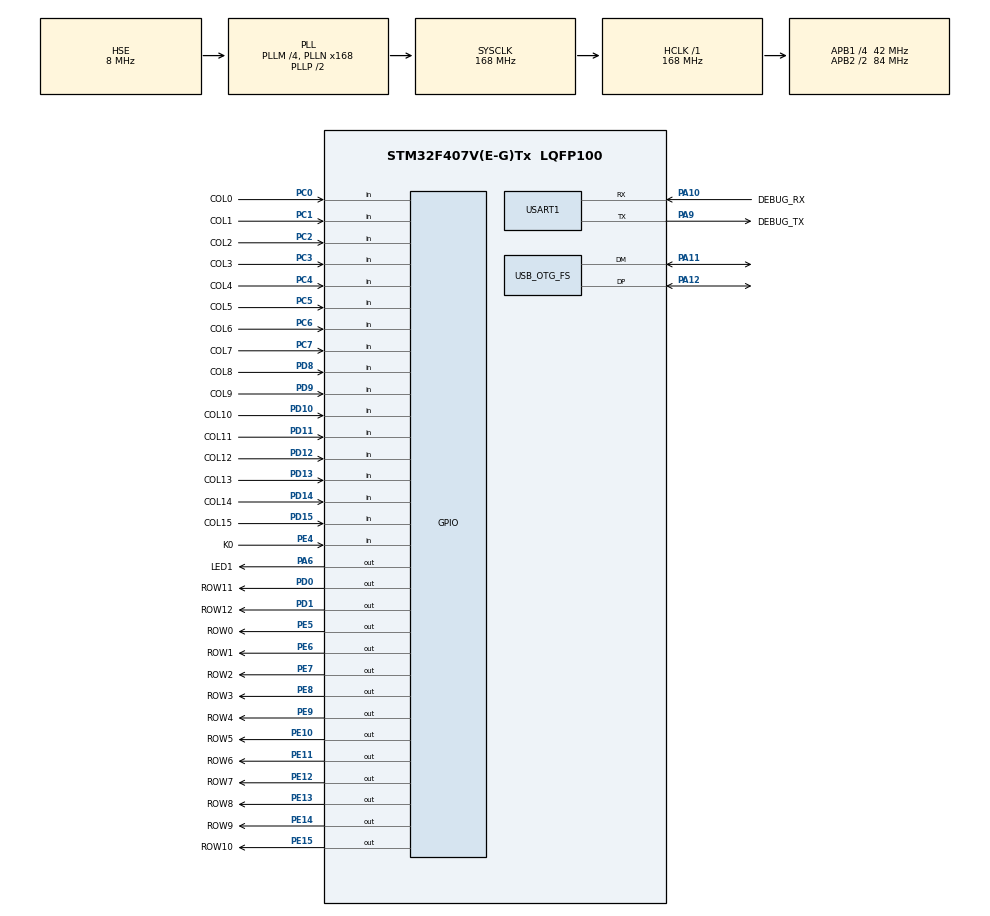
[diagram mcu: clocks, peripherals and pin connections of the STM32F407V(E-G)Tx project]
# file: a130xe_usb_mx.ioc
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Mcu.Family=STM32F4
Mcu.Name=STM32F407V(E-G)Tx
Mcu.Package=LQFP100
NVIC.OTG_FS_IRQn=true\:0\:0\:false\:false\:true\:false\:true
NVIC.PriorityGroup=NVIC_PRIORITYGROUP_4
PA10.GPIO_Label=DEBUG_RX
PA10.Mode=Asynchronous
PA10.Signal=USART1_RX
PA11.Mode=Device_Only
PA11.Signal=USB_OTG_FS_DM
PA12.Mode=Device_Only
PA12.Signal=USB_OTG_FS_DP
PA6.GPIO_Label=LED1
PA6.PinState=GPIO_PIN_SET
PA6.Signal=GPIO_Output
PA9.GPIO_Label=DEBUG_TX
PA9.Mode=Asynchronous
PA9.Signal=USART1_TX
PC0.GPIO_Label=COL0
PC0.Signal=GPIO_Input
PC1.GPIO_Label=COL1
PC1.Signal=GPIO_Input
PC2.GPIO_Label=COL2
PC2.Signal=GPIO_Input
PC3.GPIO_Label=COL3
PC3.Signal=GPIO_Input
PC4.GPIO_Label=COL4
PC4.Signal=GPIO_Input
PC5.GPIO_Label=COL5
PC5.Signal=GPIO_Input
PC6.GPIO_Label=COL6
PC6.Signal=GPIO_Input
PC7.GPIO_Label=COL7
PC7.Signal=GPIO_Input
PD0.GPIO_Label=ROW11
PD0.Signal=GPIO_Output
PD1.GPIO_Label=ROW12
PD1.Signal=GPIO_Output
PD10.GPIO_Label=COL10
PD10.Signal=GPIO_Input
PD11.GPIO_Label=COL11
PD11.Signal=GPIO_Input
PD12.GPIO_Label=COL12
PD12.Signal=GPIO_Input
PD13.GPIO_Label=COL13
PD13.Signal=GPIO_Input
PD14.GPIO_Label=COL14
PD14.Signal=GPIO_Input
PD15.GPIO_Label=COL15
PD15.Signal=GPIO_Input
PD8.GPIO_Label=COL8
PD8.Signal=GPIO_Input
PD9.GPIO_Label=COL9
PD9.Signal=GPIO_Input
PE10.GPIO_Label=ROW5
PE10.Signal=GPIO_Output
PE11.GPIO_Label=ROW6
PE11.Signal=GPIO_Output
PE12.GPIO_Label=ROW7
PE12.Signal=GPIO_Output
PE13.GPIO_Label=ROW8
PE13.Signal=GPIO_Output
PE14.GPIO_Label=ROW9
PE14.Signal=GPIO_Output
PE15.GPIO_Label=ROW10
PE15.Signal=GPIO_Output
PE4.GPIO_Label=K0
PE4.Signal=GPIO_Input
PE5.GPIO_Label=ROW0
PE5.Signal=GPIO_Output
PE6.GPIO_Label=ROW1
PE6.Signal=GPIO_Output
PE7.GPIO_Label=ROW2
PE7.Signal=GPIO_Output
PE8.GPIO_Label=ROW3
PE8.Signal=GPIO_Output
PE9.GPIO_Label=ROW4
PE9.Signal=GPIO_Output
PH0-OSC_IN.Mode=HSE-External-Oscillator
PH0-OSC_IN.Signal=RCC_OSC_IN
PH1-OSC_OUT.Mode=HSE-External-Oscillator
PH1-OSC_OUT.Signal=RCC_OSC_OUT
ProjectManager.HeapSize=0x200
ProjectManager.StackSize=0x400
ProjectManager.TargetToolchain=Makefile
RCC.48MHZClocksFreq_Value=48000000
RCC.AHBFreq_Value=168000000
RCC.APB1CLKDivider=RCC_HCLK_DIV4
RCC.APB1Freq_Value=42000000
RCC.APB1TimFreq_Value=84000000
RCC.APB2CLKDivider=RCC_HCLK_DIV2
RCC.APB2Freq_Value=84000000
RCC.APB2TimFreq_Value=168000000
RCC.CortexFreq_Value=168000000
RCC.HCLKFreq_Value=168000000
RCC.HSE_VALUE=8000000
RCC.HSI_VALUE=16000000
RCC.LSE_VALUE=32768
RCC.PLLM=4
RCC.PLLN=168
RCC.PLLQ=7
RCC.SYSCLKFreq_VALUE=168000000
RCC.SYSCLKSource=RCC_SYSCLKSOURCE_PLLCLK
RCC.VCOOutputFreq_Value=336000000
USART1.VirtualMode=VM_ASYNC
USB_DEVICE.CLASS_NAME_FS=HID
USB_DEVICE.MANUFACTURER_STRING-HID_FS=RetroBitLab
USB_DEVICE.PRODUCT_STRING_HID_FS=Keyboard Human interface
USB_DEVICE.USBD_DEBUG_LEVEL-HID_FS=3
USB_DEVICE.VirtualMode-HID_FS=Hid
USB_DEVICE.VirtualModeFS=Hid_FS
USB_OTG_FS.VirtualMode=Device_Only
VP_USB_DEVICE_VS_USB_DEVICE_HID_FS.Mode=HID_FS
board=custom

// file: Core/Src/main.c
/* USER CODE BEGIN Header */
/**
  ******************************************************************************
  * @file           : main.c
  * @brief          : Main program body
  ******************************************************************************
  * @attention
  *
  * Copyright (c) 2022 STMicroelectronics.
  * All rights reserved.
  *
  * This software is licensed under terms that can be found in the LICENSE file
  * in the root directory of this software component.
  * If no LICENSE file comes with this software, it is provided AS-IS.
  *
  ******************************************************************************
  */
/* USER CODE END Header */
#include <stdio.h>
#include <string.h>
#include "stm32f4xx_ll_gpio.h"
#include "usbd_hid.h"
#include "syscall.h"
#include "debug.h"
#include "main.h"
#include "usb_device.h"
#include "keyboard.h"
#include "host.h"
#include "config.h"

static UART_HandleTypeDef huart1;
static int debuglevel = DBG_VERBOSE;

__weak void matrix_init(void) { };

static void SystemClock_Config(void);
static void MX_GPIO_Init(void);
static void MX_USART1_UART_Init(void);

#if defined(__ATARI__)
#	define KEYBOARD_INTERFACE "ATARI XL/XE"
#elif defined(__AMIGA__)
#	define KEYBOARD_INTERFACE "AMIGA COMMODORE COMPUTERS"
#else
#	error "NO PLATFORM DEFINED"
#endif

static void banner(void)
{
	DBG_I("STM32 KEYBOARD CORE INTERFACE BOARD for " KEYBOARD_INTERFACE "\r\n");
	DBG_I("(C) RetroBit Lab 2021/2022 written by Gianluca Renzi <icjtqr@gmail.com>\r\n");
}

void led_toggle(void)
{
	static int ledval = 0;
	if (ledval == 0)
	{
		LED_ON();
	}
	else
	{
		LED_OFF();
	}
}

keyboard_type_t keyboard;
extern USBD_HandleTypeDef hUsbDeviceFS;
extern host_driver_t usbdriver;

int main(void)
{
	_write_ready(SYSCALL_NOTREADY); // printf is not functional here

	/* MCU Configuration--------------------------------------------------------*/

	/* Reset of all peripherals, Initializes the Flash interface and the Systick. */
	HAL_Init();

	/* Configure the system clock */
	SystemClock_Config();

	/* Initialize all configured peripherals */
	MX_GPIO_Init();

	MX_USART1_UART_Init();
	_write_ready(SYSCALL_READY); // printf is functional from now on...

	banner();

	MX_USB_DEVICE_Init();

	host_set_driver(&usbdriver);

	DBG_V("KEYBOARD TYPE: " KEYBOARD_INTERFACE "\r\n");

	keyboard_init();

	for(;;)
	{
		keyboard_task();
	}
}

__weak void bootloader_jump(void)
{
	DBG_E("Bootloader Jump Not Implemented Yet!\n");
	while (1);
}

void SystemClock_Config(void)
{
	RCC_OscInitTypeDef RCC_OscInitStruct = {0};
	RCC_ClkInitTypeDef RCC_ClkInitStruct = {0};

	/** Configure the main internal regulator output voltage
	*/
	__HAL_RCC_PWR_CLK_ENABLE();
	__HAL_PWR_VOLTAGESCALING_CONFIG(PWR_REGULATOR_VOLTAGE_SCALE1);
	/** Initializes the RCC Oscillators according to the specified parameters
	* in the RCC_OscInitTypeDef structure.
	*/
	RCC_OscInitStruct.OscillatorType = RCC_OSCILLATORTYPE_HSE;
	RCC_OscInitStruct.HSEState = RCC_HSE_ON;
	RCC_OscInitStruct.PLL.PLLState = RCC_PLL_ON;
	RCC_OscInitStruct.PLL.PLLSource = RCC_PLLSOURCE_HSE;
	RCC_OscInitStruct.PLL.PLLM = 4;
	RCC_OscInitStruct.PLL.PLLN = 168;
	RCC_OscInitStruct.PLL.PLLP = RCC_PLLP_DIV2;
	RCC_OscInitStruct.PLL.PLLQ = 7;
	if (HAL_RCC_OscConfig(&RCC_OscInitStruct) != HAL_OK)
	{
		Error_Handler();
	}
	/** Initializes the CPU, AHB and APB buses clocks
	*/
	RCC_ClkInitStruct.ClockType = RCC_CLOCKTYPE_HCLK|RCC_CLOCKTYPE_SYSCLK
							  |RCC_CLOCKTYPE_PCLK1|RCC_CLOCKTYPE_PCLK2;
	RCC_ClkInitStruct.SYSCLKSource = RCC_SYSCLKSOURCE_PLLCLK;
	RCC_ClkInitStruct.AHBCLKDivider = RCC_SYSCLK_DIV1;
	RCC_ClkInitStruct.APB1CLKDivider = RCC_HCLK_DIV4;
	RCC_ClkInitStruct.APB2CLKDivider = RCC_HCLK_DIV2;

	if (HAL_RCC_ClockConfig(&RCC_ClkInitStruct, FLASH_LATENCY_5) != HAL_OK)
	{
		Error_Handler();
	}
}

static void MX_USART1_UART_Init(void)
{

	huart1.Instance = USART1;
	huart1.Init.BaudRate = 115200;
	huart1.Init.WordLength = UART_WORDLENGTH_8B;
	huart1.Init.StopBits = UART_STOPBITS_1;
	huart1.Init.Parity = UART_PARITY_NONE;
	huart1.Init.Mode = UART_MODE_TX_RX;
	huart1.Init.HwFlowCtl = UART_HWCONTROL_NONE;
	huart1.Init.OverSampling = UART_OVERSAMPLING_16;
	if (HAL_UART_Init(&huart1) != HAL_OK)
	{
		Error_Handler();
	}

}

static void MX_GPIO_Init(void)
{
	GPIO_InitTypeDef GPIO_InitStruct = {0};

	/* GPIO Ports Clock Enable */
	__HAL_RCC_GPIOE_CLK_ENABLE();
	__HAL_RCC_GPIOH_CLK_ENABLE();
	__HAL_RCC_GPIOC_CLK_ENABLE();
	__HAL_RCC_GPIOA_CLK_ENABLE();
	__HAL_RCC_GPIOD_CLK_ENABLE();

	/*Configure GPIO pin Output Level */
	HAL_GPIO_WritePin(LED_CAPS_LOCK_Port, LED_CAPS_LOCK_Pin, GPIO_PIN_SET);
	HAL_GPIO_WritePin(LED_NUM_LOCK_Port, LED_NUM_LOCK_Pin, GPIO_PIN_SET);
	HAL_GPIO_WritePin(LED_SCROLL_LOCK_Port, LED_SCROLL_LOCK_Pin, GPIO_PIN_SET);
	HAL_GPIO_WritePin(LED_COMPOSE_Port, LED_COMPOSE_Pin, GPIO_PIN_SET);
	HAL_GPIO_WritePin(LED_KANA_Port, LED_KANA_Pin, GPIO_PIN_SET);

	/*Configure GPIO pin : K0_Pin Configuration 1-Atari - 0-Amiga */
	GPIO_InitStruct.Pin = K0_Pin;
	GPIO_InitStruct.Mode = GPIO_MODE_INPUT;
	GPIO_InitStruct.Pull = GPIO_PULLUP;
	HAL_GPIO_Init(K0_GPIO_Port, &GPIO_InitStruct);

	/*Configure GPIO pin : LEDS MUST BE IN THE SAME PORT! */
	GPIO_InitStruct.Pin =
		LED_CAPS_LOCK_Pin |
		LED_NUM_LOCK_Pin |
		LED_SCROLL_LOCK_Pin |
		LED_COMPOSE_Pin |
		LED_KANA_Pin;

	GPIO_InitStruct.Mode = GPIO_MODE_OUTPUT_PP;
	GPIO_InitStruct.Pull = GPIO_NOPULL;
	GPIO_InitStruct.Speed = GPIO_SPEED_FREQ_LOW;
	HAL_GPIO_Init(LEDS_GPIO_Port, &GPIO_InitStruct);

	/* The following pins are usable only on Amiga Keyboards. We are
	 * using them anyway, just to have a single firmware for more PCBs
	 * Write ONCE, Use EVERYWHERE */

	/*Configure GPIO pin : KB_DAT_Pin */
	GPIO_InitStruct.Pin = KB_DAT_Pin;
	GPIO_InitStruct.Mode = GPIO_MODE_INPUT;
	GPIO_InitStruct.Pull = GPIO_NOPULL;
	HAL_GPIO_Init(KB_DAT_GPIO_Port, &GPIO_InitStruct);

	/*Configure GPIO pins : KB_RST_Pin KB_CLK_Pin */
	GPIO_InitStruct.Pin = KB_RST_Pin;
	GPIO_InitStruct.Mode = GPIO_MODE_OUTPUT_PP;
	GPIO_InitStruct.Pull = GPIO_NOPULL;
	GPIO_InitStruct.Speed = GPIO_SPEED_FREQ_LOW;
	HAL_GPIO_Init(KB_RST_GPIO_Port, &GPIO_InitStruct);
	GPIO_InitStruct.Pin = KB_CLK_Pin;
	GPIO_InitStruct.Mode = GPIO_MODE_OUTPUT_PP;
	GPIO_InitStruct.Pull = GPIO_NOPULL;
	GPIO_InitStruct.Speed = GPIO_SPEED_FREQ_LOW;
	HAL_GPIO_Init(KB_CLK_GPIO_Port, &GPIO_InitStruct);
}

void Error_Handler(void)
{
	__disable_irq();
	while (1)
	{
	}
}

/************************ (C) COPYRIGHT STMicroelectronics *****END OF FILE****/
